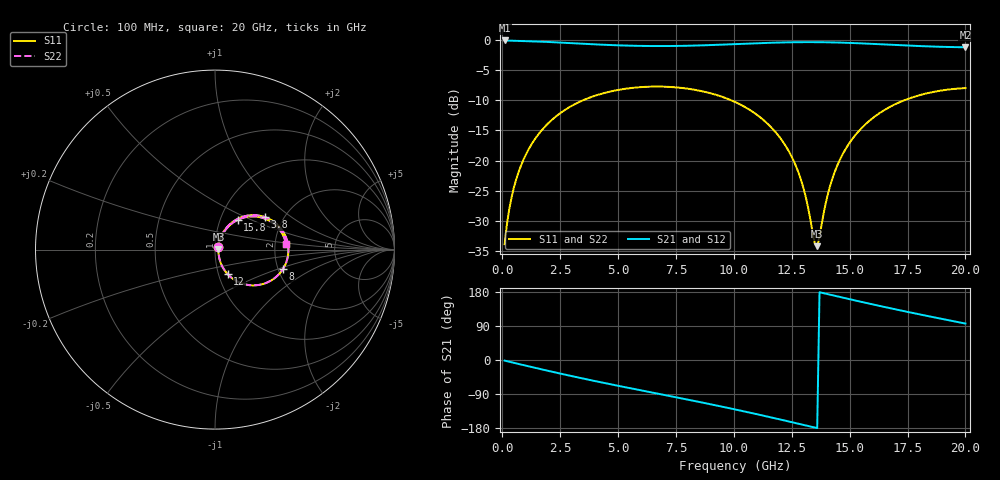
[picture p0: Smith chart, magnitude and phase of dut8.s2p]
! Touchstone file exported from HFSS 2026.1.0
!  File:  C:/ffzhzh/LocalFiles/Ansys_Project_Files/temp_test_TSV_RDL_8_1782979461_45748.aedt
!  Generated:  04:16:58 PM Jul  2, 2026
!  Design:  TSV_RDL
!  Project:  temp_test_TSV_RDL_8_1782979461_45748
! Variables:
!  h_bsmrdl = 4.33um
!  h_ox = 20um
!  h_rdl = 5um
!  h_sub = 72.61um
!  h_tmrdl = 3.27um
!  h_tsv = 72.61um
!  h_via = 3um
!  l_bsmrdl = 740.42um
!  l_sub = 4553.28um
!  l_tmrdl = 442.01um
!  m_sub = 200um
!  pitch = 45.39um
!  r_tsv = 7.15um
!  s_tmrdl = 10um
!  w_bsmrdl = 25.88um
!  w_sub = 500um
!  w_tmrdl = 28.78um
!  x_tsv_center1 = 456.4um
!  x_tsv_center2 = 1222.7um
!  x_tsv_center3 = 1693.49um
!  x_tsv_center4 = 2459.79um
!  x_tsv_center5 = 2930.58um
!  x_tsv_center6 = 3696.88um
# GHz S MA R 50.000000
! Terminal data exported
! Port[1] = TM_RDL1_1_T1
! Port[2] = TM_RDL5_1_T1
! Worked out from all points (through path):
!   200 points, 100 MHz to 20 GHz, reference 50 ohm
!   highest |S21| = -0.14 dB at 100 MHz (marker M1); lowest = -1.3 dB at 20 GHz (marker M2)
!   group delay of S21, straight-line fit = 36.5 ps
!   lowest |S11| = -34.2 dB at 13.6 GHz (marker M3), VSWR 1.04, Z = 52 + j0.272 ohm
!   |S11| at or under -10 dB: start of sweep to 3.507 GHz; 9.867 GHz to 17.38 GHz (7.518 GHz wide, 55.2 % of centre)
!   |S22| runs from -34.0 to -7.8 dB; largest |S21 - S12| = 6.7e-14
!   S11 on the Smith chart (normalised r, x): 100 MHz: 1.03, +0.03; 3.8 GHz: 1.61, +0.66; 8 GHz: 2.11, -0.55; 12 GHz: 1.11, -0.31; 15.8 GHz: 1.21, +0.42; 20 GHz: 2.30, +0.16
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0.1  0.02036 36.6  0.9839 -1.6  0.9839 -1.6  0.02036 36.6
! Gamma 0 0 0 0
! Port Impedance 50 0 50 0
0.3  0.0396 58.1  0.9812 -4.6  0.9812 -4.6  0.0396 58.1
0.5  0.0597 63.5  0.979 -7.5  0.979 -7.5  0.0597 63.5
1.1  0.1202 63.6  0.9716 -16.2  0.9716 -16.2  0.1202 63.6
2.1  0.2134 53.5  0.9538 -30.3  0.9538 -30.3  0.2134 53.5
3.5  0.3158 36.5  0.9235 -49.1  0.9235 -49.1  0.3158 36.5
3.8  0.3329 32.9  0.9173 -53.0  0.9173 -53.0  0.3329 32.9
6.8  0.4089 -2.4  0.8843 -89.9  0.8843 -89.9  0.4089 -2.4
8  0.3931 -16.3  0.8896 -104.4  0.8896 -104.4  0.3932 -16.2
10.1  0.3022 -41.2  0.9185 -131.0  0.9185 -131.0  0.3022 -41.1
12  0.154 -62.8  0.9465 -156.9  0.9465 -156.9  0.154 -62.7
12.8  0.07885 -66.8  0.9524 -168.3  0.9524 -168.3  0.07891 -66.6
13.1  0.05055 -62.7  0.9531 -172.6  0.9531 -172.6  0.05065 -62.4
13.4  0.02555 -40.2  0.9531 -176.9  0.9531 -176.9  0.02574 -39.8
13.6  0.01961 7.7  0.9525 -179.7  0.9525 -179.7  0.01984 7.5
14  0.04735 58.3  0.9504 174.5  0.9504 174.5  0.04744 58.0
14.4  0.08469 63.6  0.9468 168.9  0.9468 168.9  0.08473 63.5
15  0.1403 60.7  0.9392 160.4  0.9392 160.4  0.1404 60.6
15.8  0.2089 52.6  0.9257 149.4  0.9257 149.4  0.2089 52.6
16.7  0.275 42.3  0.9084 137.3  0.9084 137.3  0.275 42.3
18.3  0.3584 23.6  0.8802 116.9  0.8802 116.9  0.3583 23.6
20  0.3972 4.2  0.8642 96.2  0.8642 96.2  0.3972 4.2
